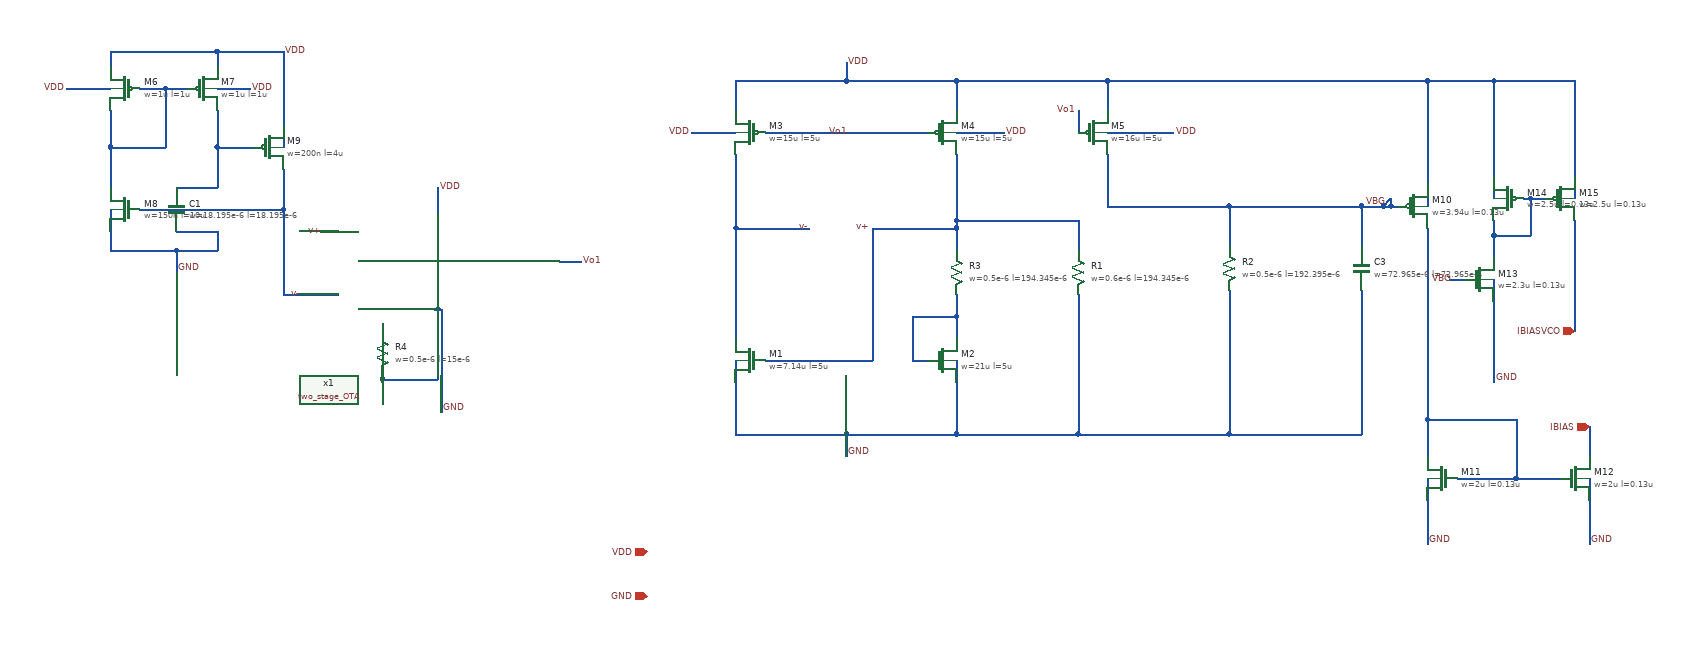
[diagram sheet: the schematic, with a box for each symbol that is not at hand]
v {xschem version=3.4.8RC file_version=1.3}
G {}
K {}
V {}
S {}
F {}
E {}
N -720 -850 -720 -795 {
lab=#net1}
N -575 -980 -485 -980 {
lab=VDD}
N -645 -930 -615 -930 {
lab=#net1}
N -720 -850 -645 -850 {
lab=#net1}
N -720 -900 -720 -850 {
lab=#net1}
N -645 -930 -645 -850 {
lab=#net1}
N -680 -930 -645 -930 {
lab=#net1}
N -720 -765 -720 -710 {
lab=GND}
N -575 -850 -575 -795 {
lab=#net2}
N -630 -710 -575 -710 {
lab=GND}
N -575 -735 -575 -710 {
lab=GND}
N -680 -765 -485 -765 {
lab=v-}
N -485 -980 -485 -850 {
lab=VDD}
N -575 -850 -525 -850 {
lab=#net2}
N -575 -900 -575 -850 {
lab=#net2}
N -485 -765 -485 -650 {
lab=v-}
N -485 -820 -485 -765 {
lab=v-}
N -110 -695 -80 -695 {
lab=Vo1}
N -275 -795 -275 -760 {
lab=VDD}
N -350 -610 -350 -595 {
lab=#net3}
N -350 -535 -275 -535 {
lab=GND}
N -275 -630 -275 -535 {
lab=GND}
N -435 -735 -410 -735 {
lab=v+}
N -485 -650 -410 -650 {
lab=v-}
N -780 -930 -720 -930 {
lab=VDD}
N -575 -930 -530 -930 {
lab=VDD}
N -575 -980 -575 -960 {
lab=VDD}
N -720 -980 -575 -980 {
lab=VDD}
N -720 -980 -720 -960 {
lab=VDD}
N 370 -560 390 -560 {
lab=#net4}
N 370 -620 370 -560 {
lab=#net4}
N 370 -620 430 -620 {
lab=#net4}
N 130 -560 130 -460 {
lab=GND}
N 280 -460 430 -460 {
lab=GND}
N 130 -740 230 -740 {
lab=v-}
N 280 -965 280 -940 {
lab=VDD}
N 130 -940 280 -940 {
lab=VDD}
N 130 -840 130 -740 {
lab=v-}
N 430 -750 430 -740 {
lab=v+}
N 430 -740 430 -710 {
lab=v+}
N 430 -560 430 -460 {
lab=GND}
N 430 -620 430 -590 {
lab=#net4}
N 430 -650 430 -620 {
lab=#net4}
N 280 -460 280 -430 {
lab=GND}
N 130 -460 280 -460 {
lab=GND}
N 170 -870 390 -870 {
lab=Vo1}
N 595 -900 595 -870 {
lab=Vo1}
N 430 -750 595 -750 {
lab=v+}
N 635 -840 635 -770 {
lab=VBG}
N 315 -740 430 -740 {
lab=v+}
N 430 -840 430 -750 {
lab=v+}
N 595 -750 595 -710 {
lab=v+}
N 430 -460 595 -460 {
lab=GND}
N 595 -650 595 -460 {
lab=GND}
N 980 -655 980 -460 {
lab=GND}
N 800 -460 980 -460 {
lab=GND}
N 980 -770 980 -715 {
lab=VBG}
N 800 -770 980 -770 {
lab=VBG}
N 635 -940 635 -900 {
lab=VDD}
N 635 -870 725 -870 {
lab=VDD}
N 430 -940 430 -900 {
lab=VDD}
N 280 -940 430 -940 {
lab=VDD}
N 430 -870 495 -870 {
lab=VDD}
N 130 -940 130 -900 {
lab=VDD}
N 70 -870 130 -870 {
lab=VDD}
N 130 -740 130 -590 {
lab=v-}
N 170 -560 315 -560 {
lab=v+}
N 315 -740 315 -560 {
lab=v+}
N 800 -770 800 -715 {
lab=VBG}
N 635 -770 800 -770 {
lab=VBG}
N 800 -655 800 -460 {
lab=GND}
N 595 -460 800 -460 {
lab=GND}
N -630 -795 -575 -795 {
lab=#net2}
N -630 -735 -575 -735 {
lab=GND}
N -350 -535 -350 -530 {lab=GND}
N -350 -540 -350 -535 {lab=GND}
N 1020 -770 1030 -770 {
lab=VBG}
N 635 -940 1070 -940 {lab=VDD}
N 430 -940 635 -940 {
lab=VDD}
N 1070 -940 1070 -770 {lab=VDD}
N 1020 -780 1020 -770 {lab=VBG}
N 1010 -770 1020 -770 {
lab=VBG}
N 1010 -770 1020 -780 {lab=VBG}
N 980 -770 1010 -770 {
lab=VBG}
N 1070 -480 1190 -480 {lab=#net5}
N 1190 -480 1190 -400 {lab=#net5}
N 1110 -400 1190 -400 {lab=#net5}
N 1290 -400 1290 -310 {lab=GND}
N 1070 -400 1070 -310 {lab=GND}
N 1190 -400 1250 -400 {lab=#net5}
N 1070 -480 1070 -430 {lab=#net5}
N 1070 -740 1070 -480 {lab=#net5}
N 1270 -940 1270 -780 {lab=VDD}
N 1160 -940 1270 -940 {lab=VDD}
N 1270 -750 1270 -600 {lab=IBIASVCO}
N 1160 -940 1160 -780 {lab=VDD}
N 1210 -780 1230 -780 {lab=#net6}
N 1160 -730 1210 -730 {lab=#net6}
N 1160 -750 1160 -730 {lab=#net6}
N 1210 -780 1210 -730 {lab=#net6}
N 1200 -780 1210 -780 {lab=#net6}
N 1070 -940 1160 -940 {lab=VDD}
N 1160 -730 1160 -700 {lab=#net6}
N 1100 -670 1120 -670 {lab=VBG}
N -630 -710 -630 -680 {
lab=GND}
N -720 -710 -630 -710 {
lab=GND}
N -275 -630 -270 -630 {lab=GND}
N -280 -630 -275 -630 {lab=GND}
N -270 -630 -270 -490 {lab=GND}
N 1160 -670 1160 -530 {lab=GND}
N 1290 -470 1290 -430 {lab=IBIAS}
C {sg13g2_pr/sg13_lv_nmos.sym} -700 -765 2 0 {name=M8
l=10u
w=150n
ng=1
m=1
model=sg13_lv_nmos
spiceprefix=X
}
C {sg13g2_pr/sg13_lv_pmos.sym} -700 -930 0 1 {name=M6
l=1u
w=1u
ng=1
m=1
model=sg13_lv_pmos
spiceprefix=X
}
C {sg13g2_pr/sg13_lv_pmos.sym} -595 -930 0 0 {name=M7
l=1u
w=1u
ng=1
m=1
model=sg13_lv_pmos
spiceprefix=X
}
C {sg13g2_pr/sg13_lv_pmos.sym} -505 -850 0 0 {name=M9
l=4u
w=200n
ng=1
m=1
model=sg13_lv_pmos
spiceprefix=X
}
C {lab_pin.sym} -485 -980 0 1 {name=p5 sig_type=std_logic lab=VDD}
C {lab_pin.sym} -275 -795 0 1 {name=p1 sig_type=std_logic lab=VDD}
C {lab_pin.sym} -530 -930 0 1 {name=p4 sig_type=std_logic lab=VDD}
C {lab_pin.sym} -780 -930 0 0 {name=p17 sig_type=std_logic lab=VDD}
C {sg13g2_pr/sg13_lv_nmos.sym} 150 -560 2 0 {name=M1
l=5u
w=7.14u
ng=4
m=1
model=sg13_lv_nmos
spiceprefix=X
}
C {sg13g2_pr/sg13_lv_nmos.sym} 410 -560 2 1 {name=M2
l=5u
w=21u
ng=8
m=1
model=sg13_lv_nmos
spiceprefix=X
}
C {sg13g2_pr/sg13_lv_pmos.sym} 150 -870 0 1 {name=M3
l=5u
w=15u
ng=8
m=1
model=sg13_lv_pmos
spiceprefix=X
}
C {sg13g2_pr/sg13_lv_pmos.sym} 410 -870 0 0 {name=M4
l=5u
w=15u
ng=8
m=1
model=sg13_lv_pmos
spiceprefix=X
}
C {lab_pin.sym} 280 -965 0 1 {name=p2 sig_type=std_logic lab=VDD}
C {lab_pin.sym} 230 -740 3 0 {name=p3 sig_type=std_logic lab=v-}
C {lab_pin.sym} 315 -740 0 0 {name=p8 sig_type=std_logic lab=v+}
C {lab_pin.sym} 285 -870 1 1 {name=p9 sig_type=std_logic lab=Vo1}
C {sg13g2_pr/sg13_lv_pmos.sym} 615 -870 0 0 {name=M5
l=5u
w=16u
ng=8
m=1
model=sg13_lv_pmos
spiceprefix=X
}
C {lab_pin.sym} 595 -900 2 1 {name=p12 sig_type=std_logic lab=Vo1}
C {lab_pin.sym} 70 -870 0 0 {name=p13 sig_type=std_logic lab=VDD}
C {lab_pin.sym} 495 -870 0 1 {name=p14 sig_type=std_logic lab=VDD}
C {lab_pin.sym} 725 -870 0 1 {name=p15 sig_type=std_logic lab=VDD}
C {sg13g2_pr/cap_cmim.sym} 980 -685 0 0 {name=C3
model=cap_cmim
w=72.965e-6
l=72.965e-6
m=1
spiceprefix=X}
C {sg13g2_pr/rppd.sym} 430 -680 0 0 {name=R3
w=0.5e-6
l=194.345e-6
model=rppd
spiceprefix=X
b=0
m=1
}
C {sg13g2_pr/rppd.sym} 595 -680 0 0 {name=R1
w=0.6e-6
l=194.345e-6
model=rppd
spiceprefix=X
b=0
m=1
}
C {sg13g2_pr/rppd.sym} 800 -685 0 0 {name=R2
w=0.5e-6
l=192.395e-6
model=rppd
spiceprefix=X
b=0
m=1
}
C {sg13g2_pr/cap_cmim.sym} -630 -765 0 0 {name=C1
model=cap_cmim
w=18.195e-6
l=18.195e-6
m=1
spiceprefix=X}
C {/foss/designs/frac-n-pll-vco-unic_cass/schematic/current_source/two_stage_OTA.sym} -260 -695 0 0 {name=x1}
C {sg13g2_pr/rppd.sym} -350 -570 0 0 {name=R4
w=0.5e-6
l=15e-6
model=rppd
spiceprefix=X
b=0
m=1
}
C {lab_pin.sym} 1015 -775 3 1 {name=p11 sig_type=std_logic lab=VBG}
C {sg13g2_pr/sg13_lv_nmos.sym} 1270 -400 0 0 {name=M12
l=0.13u
w=2u
ng=1
m=1
model=sg13_lv_nmos
spiceprefix=X
}
C {sg13g2_pr/sg13_lv_nmos.sym} 1090 -400 0 1 {name=M11
l=0.13u
w=2u
ng=1
m=1
model=sg13_lv_nmos
spiceprefix=X
}
C {sg13g2_pr/sg13_lv_pmos.sym} 1050 -770 0 0 {name=M10
l=0.13u
w=3.94u
ng=1
m=1
model=sg13_lv_pmos
spiceprefix=X
}
C {sg13g2_pr/sg13_lv_pmos.sym} 1250 -780 0 0 {name=M15
l=0.13u
w=2.5u
ng=1
m=1
model=sg13_lv_pmos
spiceprefix=X
}
C {sg13g2_pr/sg13_lv_pmos.sym} 1180 -780 0 1 {name=M14
l=0.13u
w=2.5u
ng=1
m=1
model=sg13_lv_pmos
spiceprefix=X
}
C {sg13g2_pr/sg13_lv_nmos.sym} 1140 -670 0 0 {name=M13
l=0.13u
w=2.3u
ng=1
m=1
model=sg13_lv_nmos
spiceprefix=X
}
C {lab_pin.sym} 1105 -670 1 1 {name=p18 sig_type=std_logic lab=VBG}
C {lab_pin.sym} -80 -695 2 0 {name=p10 sig_type=std_logic lab=Vo1}
C {lab_pin.sym} -460 -650 3 0 {name=p19 sig_type=std_logic lab=v-}
C {lab_pin.sym} -430 -735 1 0 {name=p7 sig_type=std_logic lab=v+}
C {lab_pin.sym} 280 -435 0 1 {name=p16 sig_type=std_logic lab=GND}
C {lab_pin.sym} -630 -685 0 1 {name=p20 sig_type=std_logic lab=GND}
C {lab_pin.sym} -270 -495 0 1 {name=p21 sig_type=std_logic lab=GND}
C {lab_pin.sym} 1070 -315 0 1 {name=p22 sig_type=std_logic lab=GND}
C {lab_pin.sym} 1290 -315 0 1 {name=p23 sig_type=std_logic lab=GND}
C {lab_pin.sym} 1160 -535 0 1 {name=p24 sig_type=std_logic lab=GND}
C {iopin.sym} 1270 -600 0 0 {name=p6 lab=IBIASVCO}
C {iopin.sym} 1290 -470 0 0 {name=p25 lab=IBIAS}
C {iopin.sym} 10 -300 0 0 {name=p26 lab=VDD}
C {iopin.sym} 10 -240 0 0 {name=p27 lab=GND}
